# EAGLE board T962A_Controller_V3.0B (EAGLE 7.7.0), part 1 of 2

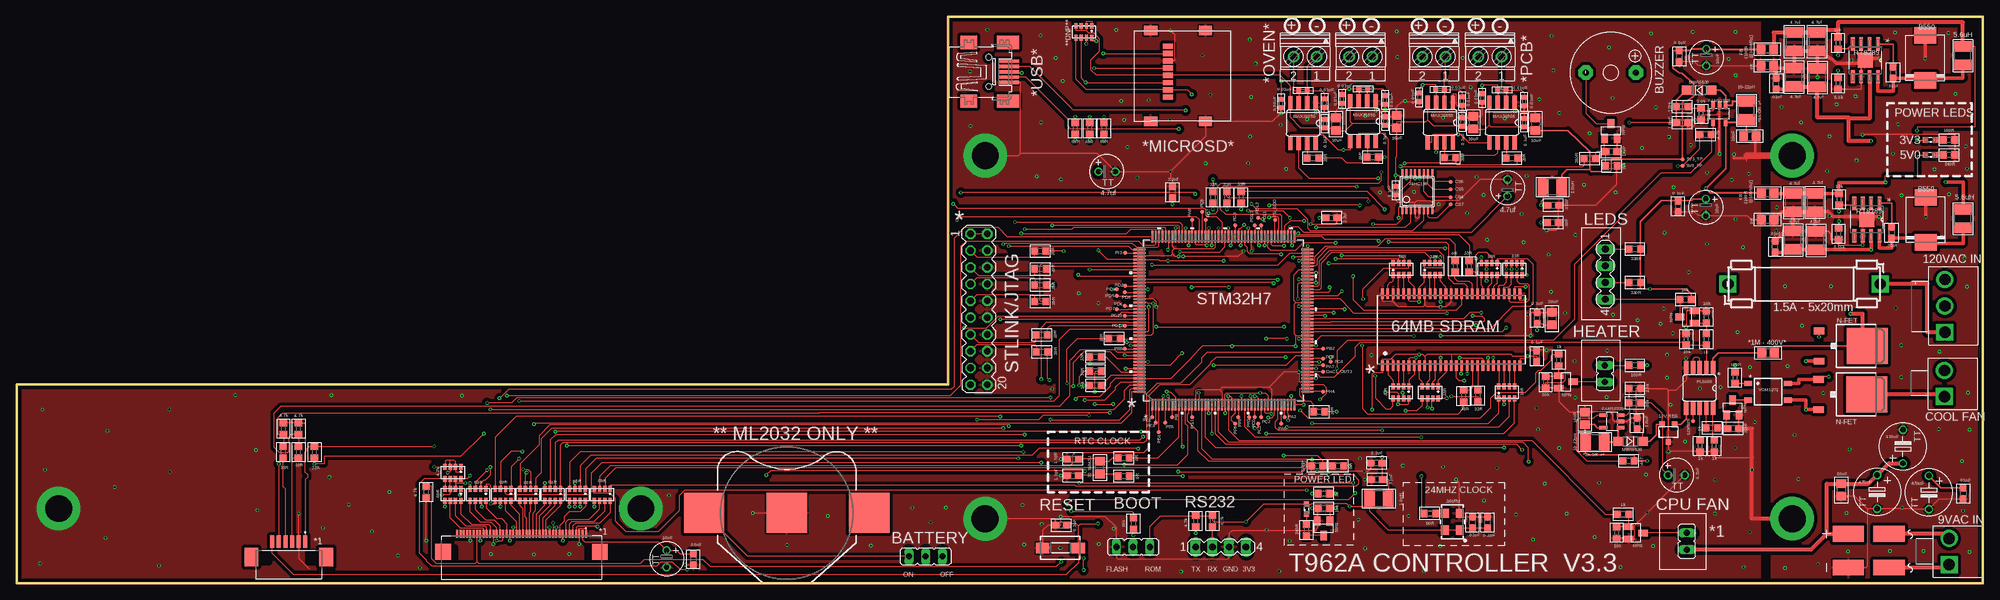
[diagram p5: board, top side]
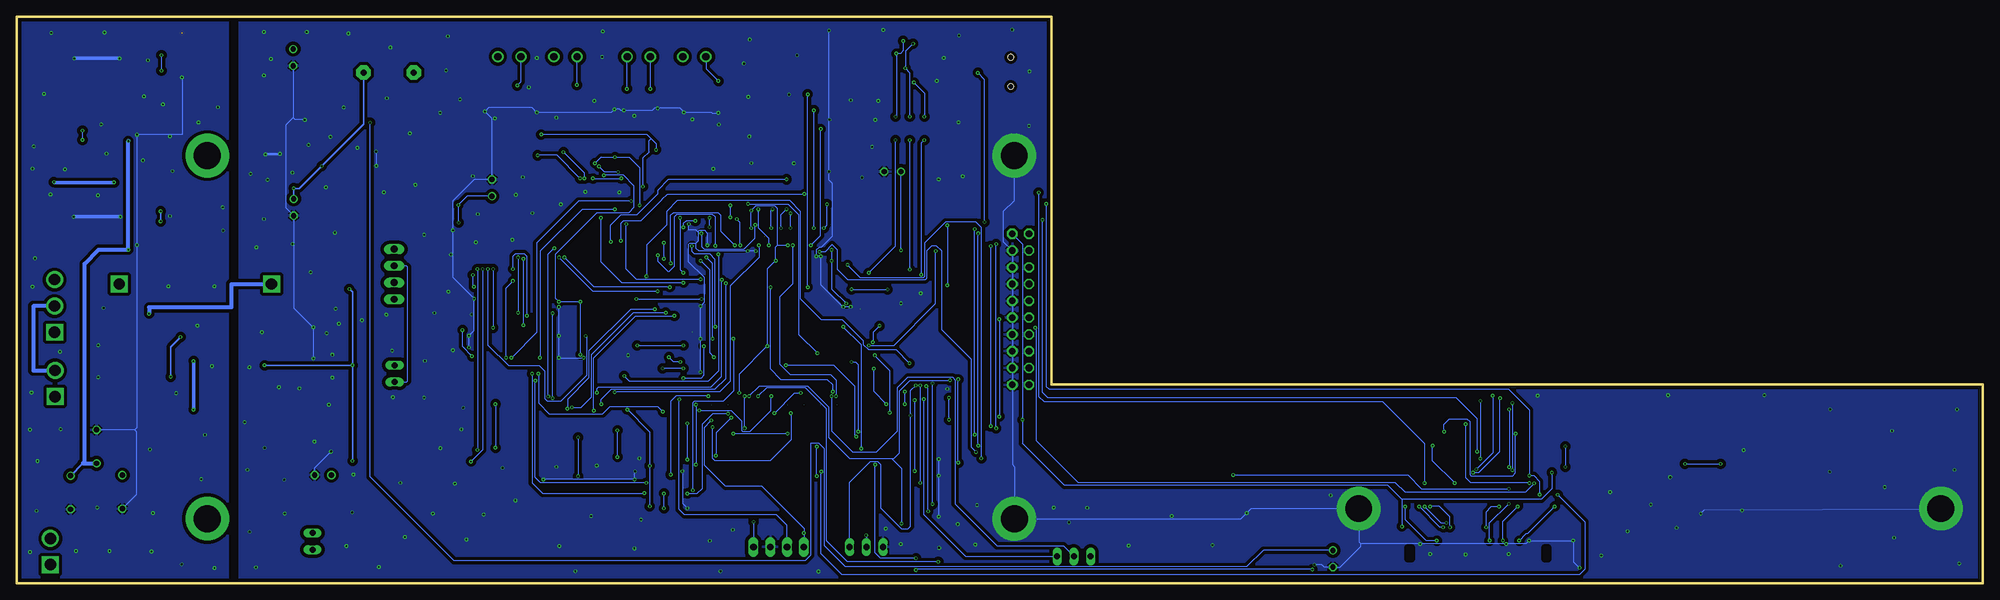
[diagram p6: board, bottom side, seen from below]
Size 297.71 x 85.85 mm. Coordinates in mm from the lower left corner, seen from the top.
Outline: 297.71,0 0,0 0,30.1 141,30.1 141,85.85 297.71,85.85 297.71,0
Copper layers (1*16): Top 0.035559375mm / dielectric 1.6mm / Bottom 0.035559375mm
Design rules "oshpark-2layer-tented": minimum track width 6mil, minimum drill 10mil, track to track 6mil, track to pad 6mil, pad to pad 6mil, via to via 6mil, smd to smd 6mil, copper to edge 15mil, drill to drill 6mil, minimum pad ring 5mil, minimum via ring 5mil, stop-mask expansion 2.5mil, vias tented up to drill 20mil, thermal gap 10mil

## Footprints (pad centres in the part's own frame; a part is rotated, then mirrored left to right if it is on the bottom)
Z4-D = smd 2.4 x 4.7: AC1 2.55,-3.1; AC2 -2.55,-3.1; VDD 2.55,3.1; VSS -2.55,3.1
BATTCON_20MM = smd 6.07 x 6.07: 1 -12.5,0; 2 0,0; 3 12.5,0
TT5D7 = drill 0.813: + -2.54,0 | drill 0.813 octagon: - 2.54,0
C0603 = smd 1.1 x 1: 1 -0.85,0; 2 0.85,0
TT2D5 = drill 0.813: + -1.27,0 | drill 0.813 octagon: - 1.27,0
C0805 = smd 1.3 x 1.5: 1 -0.95,0; 2 0.95,0
C0402 = smd 0.7 x 0.9: 1 -0.65,0; 2 0.65,0
C1210 = smd 1.6 x 2.7: 1 -1.4,0; 2 1.4,0
SOD123 = smd 1.4 x 1.4: A -1.9,0; C 1.9,0
FUSE_HOLDER_5X20MM_1.78MM = drill 1.707 square: 1 -2.565,0; 2 20.498,0.025
SOT23-3 = smd 0.8 x 0.9: 1 -0.95,-1; 2 0.95,-1; 3 0,1.659
TSSOP16 = smd 0.305 x 0.991: 1 -2.275,-2.918; 2 -1.625,-2.918; 3 -0.975,-2.918; 4 -0.325,-2.918; 5 0.325,-2.918; 6 0.975,-2.918; 7 1.625,-2.918; 8 2.275,-2.918; 9 2.275,2.918; 10 1.625,2.918; 11 0.975,2.918; 12 0.325,2.918; 13 -0.325,2.918; 14 -0.975,2.918; 15 -1.625,2.918; 16 -2.275,2.918
MOLEX_54104-4031-REV = smd 0.3 x 1.2: 1 9.75,0.6; 2 9.25,0.6; 3 8.75,0.6; 4 8.25,0.6; 5 7.75,0.6; 6 7.25,0.6; 7 6.75,0.6; 8 6.25,0.6; 9 5.75,0.6; 10 5.25,0.6; 11 4.75,0.6; 12 4.25,0.6; 13 3.75,0.6; 14 3.25,0.6; 15 2.75,0.6; 16 2.25,0.6; 17 1.75,0.6; 18 1.25,0.6; 19 0.75,0.6; 20 0.25,0.6; 21 -0.25,0.6; 22 -0.75,0.6; 23 -1.25,0.6; 24 -1.75,0.6; 25 -2.25,0.6; 26 -2.75,0.6; 27 -3.25,0.6; 28 -3.75,0.6; 29 -4.25,0.6; 30 -4.75,0.6; 31 -5.25,0.6; 32 -5.75,0.6; 33 -6.25,0.6; 34 -6.75,0.6; 35 -7.25,0.6; 36 -7.75,0.6; 37 -8.25,0.6; 38 -8.75,0.6; 39 -9.25,0.6; 40 -9.75,0.6 | smd 2.4 x 2.4: FITTING_NAIL_1 -11.85,-2.1; FITTING_NAIL_2 11.85,-2.1
KK41791-4020_2-PIN = drill 1.707 square: 1 -1.981,0 | drill 1.707: 2 1.981,0
MOLEX_52271-0679_REV = smd 0.6 x 1.9: 1 2.5,3.5; 2 1.5,3.5; 3 0.5,3.5; 4 -0.5,3.5; 5 -1.5,3.5; 6 -2.5,3.5 | smd 2.1 x 2.8: FITTING_NAIL_1 -5.65,1.15; FITTING_NAIL_2 5.65,1.15
KK41791-4020_3-PIN = drill 1.707 square: 1 -1.981,0 | drill 1.707: 2 1.981,0; 3 5.994,0
JP2_NOLABEL = drill 0.914 long: 1 -2.54,0; 2 0,0; 3 2.54,0
JP1 = drill 0.914 long: 1 0,-1.27; 2 0,1.27
L0805 = smd 1.3 x 1.5: 1 -0.95,0; 2 0.95,0
R1210 = smd 1.6 x 2.7: 1 -1.4,0; 2 1.4,0
SML0603 = smd 0.8 x 0.8: A 0.75,0; C -0.75,0
R0603 = smd 1 x 1.1: 1 -0.85,0; 2 0.85,0
R0805 = smd 1.3 x 1.5: 1 -0.95,0; 2 0.95,0
742-8NS-REV = smd 0.5 x 0.9: 1 1.2,-0.9; 2 0.4,-0.9; 3 -0.4,-0.9; 4 -1.2,-0.9; 5 -1.2,0.9; 6 -0.4,0.9; 7 0.4,0.9; 8 1.2,0.9
742-8NS = smd 0.5 x 0.9: 1 -1.2,-0.9; 2 -0.4,-0.9; 3 0.4,-0.9; 4 1.2,-0.9; 5 1.2,0.9; 6 0.4,0.9; 7 -0.4,0.9; 8 -1.2,0.9
DTSM-3 = smd 2 x 1.6: 1 -2.7,0; 2 2.7,0
YHE12-XX-7.6MM = drill 0.914 pad 2.159 octagon: + 3.81,0.025; - -3.81,0.025
MA10-2 = drill 1.016 octagon: 1 -11.43,-1.27; 2 -11.43,1.27; 3 -8.89,-1.27; 4 -8.89,1.27; 5 -6.35,-1.27; 6 -6.35,1.27; 7 -3.81,-1.27; 8 -3.81,1.27; 9 -1.27,-1.27; 10 -1.27,1.27; 11 1.27,-1.27; 12 1.27,1.27; 13 3.81,-1.27; 14 3.81,1.27; 15 6.35,-1.27; 16 6.35,1.27; 17 8.89,-1.27; 18 8.89,1.27; 19 11.43,-1.27; 20 11.43,1.27
MA04-1 = drill 1.016 long: 1 -3.81,0; 2 -1.27,0; 3 1.27,0; 4 3.81,0
SOT23-BEC = smd 1 x 1.4: B -0.95,-1.1; C 0,1.1; E 0.95,-1.1
TP06R = smd 0.6 x 0.6: TP 0,0
LQFP176-24X24MM-M = smd 1.778 x 0.279: 1 -12.725,10.75; 2 -12.725,10.25; 3 -12.725,9.75; 4 -12.725,9.25; 5 -12.725,8.75; 6 -12.725,8.25; 7 -12.725,7.75; 8 -12.725,7.25; 9 -12.725,6.75; 10 -12.725,6.25; 11 -12.725,5.75; 12 -12.725,5.25; 13 -12.725,4.75; 14 -12.725,4.25; 15 -12.725,3.75; 16 -12.725,3.25; 17 -12.725,2.75; 18 -12.725,2.25; 19 -12.725,1.75; 20 -12.725,1.25; 21 -12.725,0.75; 22 -12.725,0.25; 23 -12.725,-0.25; 24 -12.725,-0.75; 25 -12.725,-1.25; 26 -12.725,-1.75; 27 -12.725,-2.25; 28 -12.725,-2.75; 29 -12.725,-3.25; 30 -12.725,-3.75; 31 -12.725,-4.25; 32 -12.725,-4.75; 33 -12.725,-5.25; 34 -12.725,-5.75; 35 -12.725,-6.25; 36 -12.725,-6.75; 37 -12.725,-7.25; 38 -12.725,-7.75; 39 -12.725,-8.25; 40 -12.725,-8.75; 41 -12.725,-9.25; 42 -12.725,-9.75; 43 -12.725,-10.25; 44 -12.725,-10.75; 89 12.725,-10.75; 90 12.725,-10.25; 91 12.725,-9.75; 92 12.725,-9.25; 93 12.725,-8.75; 94 12.725,-8.25; 95 12.725,-7.75; 96 12.725,-7.25; 97 12.725,-6.75; 98 12.725,-6.25; 99 12.725,-5.75; 100 12.725,-5.25; 101 12.725,-4.75; 102 12.725,-4.25; 103 12.725,-3.75; 104 12.725,-3.25; 105 12.725,-2.75; 106 12.725,-2.25; 107 12.725,-1.75; 108 12.725,-1.25; 109 12.725,-0.75; 110 12.725,-0.25; 111 12.725,0.25; 112 12.725,0.75; 113 12.725,1.25; 114 12.725,1.75; 115 12.725,2.25; 116 12.725,2.75; 117 12.725,3.25; 118 12.725,3.75; 119 12.725,4.25; 120 12.725,4.75; 121 12.725,5.25; 122 12.725,5.75; 123 12.725,6.25; 124 12.725,6.75; 125 12.725,7.25; 126 12.725,7.75; 127 12.725,8.25; 128 12.725,8.75; 129 12.725,9.25; 130 12.725,9.75; 131 12.725,10.25; 132 12.725,10.75 | smd 0.279 x 1.778: 45 -10.75,-12.725; 46 -10.25,-12.725; 47 -9.75,-12.725; 48 -9.25,-12.725; 49 -8.75,-12.725; 50 -8.25,-12.725; 51 -7.75,-12.725; 52 -7.25,-12.725; 53 -6.75,-12.725; 54 -6.25,-12.725; 55 -5.75,-12.725; 56 -5.25,-12.725; 57 -4.75,-12.725; 58 -4.25,-12.725; 59 -3.75,-12.725; 60 -3.25,-12.725; 61 -2.75,-12.725; 62 -2.25,-12.725; 63 -1.75,-12.725; 64 -1.25,-12.725; 65 -0.75,-12.725; 66 -0.25,-12.725; 67 0.25,-12.725; 68 0.75,-12.725; 69 1.25,-12.725; 70 1.75,-12.725; 71 2.25,-12.725; 72 2.75,-12.725; 73 3.25,-12.725; 74 3.75,-12.725; 75 4.25,-12.725; 76 4.75,-12.725; 77 5.25,-12.725; 78 5.75,-12.725; 79 6.25,-12.725; 80 6.75,-12.725; 81 7.25,-12.725; 82 7.75,-12.725; 83 8.25,-12.725; 84 8.75,-12.725; 85 9.25,-12.725; 86 9.75,-12.725; 87 10.25,-12.725; 88 10.75,-12.725; 133 10.75,12.725; 134 10.25,12.725; 135 9.75,12.725; 136 9.25,12.725; 137 8.75,12.725; 138 8.25,12.725; 139 7.75,12.725; 140 7.25,12.725; 141 6.75,12.725; 142 6.25,12.725; 143 5.75,12.725; 144 5.25,12.725; 145 4.75,12.725; 146 4.25,12.725; 147 3.75,12.725; 148 3.25,12.725; 149 2.75,12.725; 150 2.25,12.725; 151 1.75,12.725; 152 1.25,12.725; 153 0.75,12.725; 154 0.25,12.725; 155 -0.25,12.725; 156 -0.75,12.725; 157 -1.25,12.725; 158 -1.75,12.725; 159 -2.25,12.725; 160 -2.75,12.725; 161 -3.25,12.725; 162 -3.75,12.725; 163 -4.25,12.725; 164 -4.75,12.725; 165 -5.25,12.725; 166 -5.75,12.725; 167 -6.25,12.725; 168 -6.75,12.725; 169 -7.25,12.725; 170 -7.75,12.725; 171 -8.25,12.725; 172 -8.75,12.725; 173 -9.25,12.725; 174 -9.75,12.725; 175 -10.25,12.725; 176 -10.75,12.725
SOT23-5L = smd 0.55 x 1.2: 1 -0.95,-1.3; 2 0,-1.3; 3 0.95,-1.3; 4 0.95,1.3; 5 -0.95,1.3
SO08 = smd 0.66 x 2.032: 1 -1.905,-3.073; 2 -0.635,-3.073; 3 0.635,-3.073; 4 1.905,-3.073; 5 1.905,3.073; 6 0.635,3.073; 7 -0.635,3.073; 8 -1.905,3.073
SOIC127P600X175-9N = smd 1.981 x 0.559: 1 -2.464,1.905; 2 -2.464,0.635; 3 -2.464,-0.635; 4 -2.464,-1.905; 5 2.464,-1.905; 6 2.464,-0.635; 7 2.464,0.635; 8 2.464,1.905 | smd 2.286 x 2.286: 9 0,0
DO214AB-SMC = smd 2.5 x 3.3: A 3.4,0; C -3.4,0
SOP10 = smd 0.66 x 2.032: 1 -2.057,-3.073; 2 -1.041,-3.073; 3 -0.025,-3.073; 4 0.991,-3.073; 5 2.007,-3.073; 6 2.007,3.073; 7 0.991,3.073; 8 -0.025,3.073; 9 -1.041,3.073; 10 -2.057,3.073
DPACK_3 = smd 1 x 1.6: 1 -2.28,-4.8; 3 2.28,-4.8 | smd 5.4 x 6.2: 4 0,2.5
SOP04 = smd 0.8 x 1.2: 1 -1.27,-3; 2 1.27,-3; 3 1.27,3; 4 -1.27,3
TSOP54 = smd 0.4 x 1.6: 1 -10.4,-5.45; 2 -9.6,-5.45; 3 -8.8,-5.45; 4 -8,-5.45; 5 -7.2,-5.45; 6 -6.4,-5.45; 7 -5.6,-5.45; 8 -4.8,-5.45; 9 -4,-5.45; 10 -3.2,-5.45; 11 -2.4,-5.45; 12 -1.6,-5.45; 13 -0.8,-5.45; 14 0,-5.45; 15 0.8,-5.45; 16 1.6,-5.45; 17 2.4,-5.45; 18 3.2,-5.45; 19 4,-5.45; 20 4.8,-5.45; 21 5.6,-5.45; 22 6.4,-5.45; 23 7.2,-5.45; 24 8,-5.45; 25 8.8,-5.45; 26 9.6,-5.45; 27 10.4,-5.45; 28 10.4,5.45; 29 9.6,5.45; 30 8.8,5.45; 31 8,5.45; 32 7.2,5.45; 33 6.4,5.45; 34 5.6,5.45; 35 4.8,5.45; 36 4,5.45; 37 3.2,5.45; 38 2.4,5.45; 39 1.6,5.45; 40 0.8,5.45; 41 0,5.45; 42 -0.8,5.45; 43 -1.6,5.45; 44 -2.4,5.45; 45 -3.2,5.45; 46 -4,5.45; 47 -4.8,5.45; 48 -5.6,5.45; 49 -6.4,5.45; 50 -7.2,5.45; 51 -8,5.45; 52 -8.8,5.45; 53 -9.6,5.45; 54 -10.4,5.45
MOLEX:47219-2001 = smd 1.45 x 2: G1 13.75,0; G2 13.75,8.3; G3 0,8.3; G4 0,0 | smd 0.8 x 1.5: P1 10.08,2.6; P2 8.98,2.6; P3 7.88,2.6; P4 6.78,2.6; P5 5.68,2.6; P6 4.58,2.6; P7 3.48,2.6; P8 2.38,2.6
1751248 = drill 1.1 pad 1.7: 1 -1.75,-0.1; 2 1.75,-0.1
32005-201 = smd 3.1 x 0.5: 1 3,1.6; 2 3,0.8; 3 3,0; 4 3,-0.8; 5 3,-1.6 | smd 2.5 x 2: M1 -3,-4.45; M2 -3,4.45 | smd 3.3 x 2: M3 2.9,4.45; M4 2.9,-4.45 | hole 0.9: 0,2.2; 0,-2.2
OSCILLATOR-SMD-5X3.2 = smd 1.397 x 1.194: 1 -1.27,-1.1; 2 1.27,-1.1; 3 1.27,1.1; 4 -1.27,1.1

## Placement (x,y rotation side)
B1  Z4DGP406L-HF  [Z4-D]  280.39,4.93 90 top
BT1  [BATTCON_20MM]  116.61,10.64 0 top
C1  470uF  [TT5D7]  289.53,13.74 270 top
C2  0.1uF  [C0603]  205.89,18.21 180 top
C3  10uF  [TT2D5]  255.83,79.65 270 top
C4  0.01uF  [C0603]  205.97,15.72 180 top
C5  .1uf  [C0603]  158.17,8.79 180 top
C6  470uF  [TT5D7]  281.69,13.84 270 top
C7  10uF  [C0805]  276.28,14.12 270 top
C8  0.1uF  [C0603]  222.71,9.22 90 top
C9  2.2uF  [C0603]  175.01,59.23 90 top
C10  2.2uF  [C0603]  199.09,55.37 0 top
C11  10uF  [TT2D5]  255.75,56.95 270 top
C12  0.01uF  [C0603]  220.42,9.22 90 top
C13  .1uf  [C0603]  230.2,40.18 90 top
C14  .1uf  [C0603]  230.15,34.39 90 top
C15  1.0uF  [C0603]  252.17,69.77 0 top
C16  0.1uF  [C0603]  251.71,79.83 270 top
C17  0.1uF  [C0603]  251.54,57.1 270 top
C18  10uF  [C0805]  262.41,67.72 0 top
C19  0.01uF  [C0402]  203.89,74.9 180 top
C20  0.01uF  [C0402]  200.66,73.36 90 top
C21  0.01uF  [C0402]  207.19,73.2 90 top
C22  0.01uF  [C0402]  215.52,74.8 180 top
C23  0.01uF  [C0402]  212.37,73.61 90 top
C24  1.5pf  [C0603]  159.92,18.82 0 top
C25  1.5pf  [C0603]  159.92,16.31 0 top
C26  0.1uF  [C0603]  232.61,54.64 0 top
C27  22nf  [C0603]  259.89,23.44 180 top
C28  470uF  [TT5D7]  285.6,20.7 90 top
C29  0.01uF  [C0603]  232.66,57.28 0 top
C30  1.0uF  [C0603]  245.34,24.23 90 top
C31  0.1uF  [C0402]  208.79,59.49 270 top
C32  0.1uF  [C0402]  207.21,70.03 270 top
C33  0.1uF  [C0402]  218.87,69.88 270 top
C34  10uF  [C0805]  237.44,24.99 90 top
C35  0.1uF  [C0402]  228.24,69.77 270 top
C36  0.1uF  [C0402]  198.07,69.62 270 top
C37  4.7uF  [TT2D5]  251.31,16.38 0 top
C38  4.7uF  [TT2D5]  165.07,62.36 0 top
C39  4.7uF  [TT2D5]  225.73,59.89 90 top
C40  10uF  [TT2D5]  98.42,3.71 270 top
C41  .01uF  [C0603]  102.44,3.63 270 top
C42  10uF  [C0805]  232.46,40.08 90 top
C45  DNP  [C0603]  241.43,65.38 180 top
C46  10uF  [C0805]  199.72,69.55 270 top
C47  10uF  [C0805]  208.94,69.9 270 top
C48  0.01uF  [C0402]  191.44,72.67 90 top
C49  10uF  [C0805]  220.55,69.77 270 top
C50  .01uF  [C0603]  294.72,13.61 270 top
C51  10uF  [C0805]  229.97,69.55 270 top
C52  0.01uF  [C0402]  198.04,72.75 90 top
C53  0.01uF  [C0402]  194.77,74.63 180 top
C54  .01uF  [C0603]  284.1,77.37 270 top
C55  .01uF  [C0603]  266.4,75.69 90 top
C56  4.7uF  [C1210]  272.64,76.58 90 top
C57  4.7uF  [C1210]  269.09,76.66 90 top
C58  47uf  [C1210]  269.14,82.02 270 top
C59  47uf  [C1210]  272.59,82.02 270 top
C60  0.01uF  [C0402]  218.85,73.03 90 top
C61  0.01uF  [C0402]  224.89,74.73 180 top
C62  0.01uF  [C0402]  221.89,73.51 90 top
C63  0.01uF  [C0402]  228.24,72.95 90 top
C88  .01uF  [C0603]  283.87,53.11 270 top
C89  .01uF  [C0603]  266.24,50.98 90 top
C90  4.7uF  [C1210]  272.41,51.92 90 top
C91  4.7uF  [C1210]  268.94,51.99 90 top
C92  47uf  [C1210]  272.29,57.68 270 top
C93  47uf  [C1210]  269.01,57.63 270 top
D1  MBR0520LT  [SOD123]  254.71,74.68 180 top
D2  MBR0520LT  [SOD123]  244.35,21.49 0 top
F1  FUSE  [FUSE_HOLDER_5X20MM_1.78MM]  261.67,45.31 0 top
IC1  TLV760SOT-23-3  [SOT23-3]  250.09,23.06 180 top
IC2  74138TSSOP  [TSSOP16]  212.06,59.31 0 top
J1  54104-4031MOLEX_54101_4031-REV  [MOLEX_54104-4031-REV]  76.45,6.86 0 top
J2  0026604020  [KK41791-4020_2-PIN]  292.58,4.8 90 top
J3  52271-0679_REVMOLEX_52271-0679-REV  [MOLEX_52271-0679_REV]  41.22,2.84 0 top
J4  0026604030  [KK41791-4020_3-PIN]  291.95,40.01 90 top
J5  0026604020  [KK41791-4020_2-PIN]  291.87,30.25 90 top
JP1  [JP2_NOLABEL]  169.04,5.49 0 top
JP2  [JP1]  240.46,31.75 0 top
JP3  [JP1]  252.88,6.35 180 top
JP4  [JP2_NOLABEL]  137.64,4.06 180 top
L1  100R@100Mhz  [L0805]  265.1,59.11 180 top
L2  5.6uH  [R1210]  294.67,79.91 90 top
L3  5.6uH  [R1210]  294.69,55.22 90 top
L4  10uH  [R1210]  206.27,12.85 0 top
L6  100R@100Mhz  [L0805]  265.07,80.92 180 top
L8  10uH  [R1210]  232.54,60.02 180 top
LED1  [SML0603]  289.74,67.16 180 top
LED2  [SML0603]  195.3,11.23 90 top
LED5  [SML0603]  289.71,64.87 180 top
Q1  32.768Khz  [C0805]  164.01,17.53 90 top
R1  20R  [R0603]  154.99,50.32 180 top
R2  100R  [R0603]  292.56,67.16 0 top
R3  20R  [R0603]  155.02,47.62 180 top
R4  20R  [R0603]  155.02,45.16 180 top
R5  240R  [R0603]  292.58,64.87 180 top
R6  0R  [R0805]  265.1,55.12 180 top
R7  20R  [R0603]  154.99,42.7 180 top
R8  20R  [R0603]  155.19,37.62 180 top
R9  20R  [R0603]  155.24,35.05 180 top
R10  10k  [R0603]  163.35,29.97 0 top
R11  10k  [R0603]  169.09,9.04 90 top
R12  33R  [R0603]  219.94,48.03 270 top
R13  0R  [R0603]  167.61,19 180 top
R14  50R  [R0603]  213.97,10.57 0 top
R15  0R  [R0603]  217.78,48.03 270 top
R16  33R  [R0603]  181.13,58.45 90 top
R17  20R  [R0603]  205.33,64.54 180 top
R18  20R  [R0603]  217.04,64.47 180 top
R19  20R  [R0603]  226.39,64.39 180 top
R20  1k  [R0603]  256.67,23.52 0 top
R21  10k  [R0603]  252.78,36.98 90 top
R22  100R  [R0603]  245.01,33.02 180 top
R23  4.7k  [R0603]  178.51,9.4 270 top
R24  4.7k  [R0603]  181.05,9.4 270 top
R25  100R  [R0603]  260.17,31.14 90 top
R26  2.0k  [R0603]  245.01,29.51 0 top
R27  20R  [R0603]  196.27,64.41 180 top
R28  2k  [R0603]  197.92,13.59 180 top
R29  240R  [R0603]  195.3,8.08 270 top
R30  10k  [R0603]  197.92,11.35 0 top
R31  10K  [R0603]  275.77,81.81 270 top
R32  5.6k  [R0603]  275.77,75.69 270 top
R33  10K  [R0603]  275.92,58.17 270 top
R34  3.16k  [R0603]  275.84,52.91 270 top
R35  10k  [R0603]  241.45,63.22 180 top
R36  4k7  [R0603]  42.7,23.42 90 top
R37  4K7  [R0603]  255.7,67.97 0 top
R38  4k7  [R0603]  62.03,13.79 270 top
R39  0R  [R0805]  265.07,78.41 180 top
R40  1M  [R0805]  265.18,34.9 0 top
R41  4k7  [R0603]  40.41,23.42 90 top
R42  33R  [R0603]  221.23,28.4 90 top
R43  390R  [R0603]  238.18,64.34 180 top
R44  10k  [R0603]  255.83,40.34 90 top
R45  120k  [R0603]  252.17,72.21 180 top
R46  4K7  [R0603]  244.04,18.54 180 top
R47  80k  [R0603]  245.01,27.3 0 top
R48  68R  [R0603]  164.64,68.91 90 top
R49  68R  [R0603]  162.48,68.91 90 top
R50  68R  [R0603]  160.27,68.91 90 top
R51  33R  [R0603]  42.7,19.86 270 top
R52  1k  [R0603]  243.2,10.44 0 top
R53  10k  [R0603]  242.24,7.65 90 top
R54  1k  [R0603]  233.48,33.83 270 top
R55  10k  [R0603]  231.5,30.45 90 top
R56  330R  [R0603]  245.01,50.62 180 top
R57  330R  [R0603]  245.01,45.54 180 top
R58  10k  [R0603]  252.7,42.98 0 top
R59  0R  [R0603]  200.08,17.78 0 top
R60  DNP  [R0603]  196.93,17.78 0 top
R61  2.0k  [R0603]  255.04,71.07 270 top
R62  1k  [R0603]  254.86,20.8 90 top
R63  1k  [R0603]  257.02,20.8 90 top
R64  1k  [R0603]  255.83,36.98 90 top
R65  33R  [R0603]  40.39,19.86 270 top
R66  4k7  [R0603]  45.11,19.86 90 top
R67  33R  [R0603]  219.07,28.37 90 top
R68  33R  [R0603]  166.22,37.08 180 top
R69  33R  [R0603]  197.21,25.98 0 top
R70  33R  [R0603]  163.35,34.29 180 top
R71  33R  [R0603]  163.35,32.13 180 top
R72  33R  [R0603]  183.26,58.45 90 top
R73  33R  [R0603]  185.39,58.45 90 top
R74  0R  [R0603]  167.61,16.23 180 top
RN1  33R  [742-8NS-REV]  209.63,47.57 0 top
RN2  33R  [742-8NS-REV]  214.35,47.57 0 top
RN3  33R  [742-8NS-REV]  214.02,28.91 180 top
RN4  33R  [742-8NS-REV]  209.6,28.91 180 top
RN5  33R  [742-8NS]  225.6,28.91 0 top
RN6  4.7k  [742-8NS]  66.07,16.74 180 top
RN7  33R  [742-8NS]  226.75,47.57 180 top
RN8  33R  [742-8NS]  222.96,47.57 180 top
RN11  **DNP**  [742-8NS]  161.59,83.52 180 top
RN12  68R  [742-8NS-REV]  88.67,13.41 180 top
RN13  68R  [742-8NS-REV]  84.94,13.41 180 top
RN14  68R  [742-8NS-REV]  81.18,13.41 180 top
RN15  68R  [742-8NS-REV]  77.42,13.41 180 top
RN16  68R  [742-8NS-REV]  73.66,13.41 180 top
RN17  68R  [742-8NS-REV]  69.88,13.41 180 top
RN18  68R  [742-8NS-REV]  66.07,13.41 180 top
S1  DTSM-3  [DTSM-3]  158.04,5.36 0 top
SG1  YHE12-XX7.6MM  [YHE12-XX-7.6MM]  241.38,77.34 0 top
SV1  [MA10-2]  145.69,41.5 270 top
SV3  [MA04-1]  240.54,46.81 270 top
SV5  RS232  [MA04-1]  182.32,5.49 0 top
T1  BC817-16LT1SMD  [SOT23-BEC]  241.38,68.5 0 top
T3  BC817-16LT1SMD  [SOT23-BEC]  197.89,8.33 180 top
T4  BC817-16LT1SMD  [SOT23-BEC]  245.16,7.62 270 top
T5  BC817-16LT1SMD  [SOT23-BEC]  234.57,30.51 270 top
T6  BC817-16LT1SMD  [SOT23-BEC]  259.82,26.62 0 top
T7  BC817-16LT1SMD  [SOT23-BEC]  252.93,40.34 90 top
TP1  TPTP06R  [TP06R]  187.48,25.17 0 top
TP2  TPTP06R  [TP06R]  187.99,24.16 0 top
TP3  TPTP06R  [TP06R]  198.93,33.53 0 top
TP4  TPTP06R  [TP06R]  252.22,64.21 0 top
TP5  TPTP06R  [TP06R]  188.47,25.17 0 top
TP6  TPTP06R  [TP06R]  217.12,57.4 0 top
TP7  TPTP06R  [TP06R]  217.12,60.83 0 top
TP8  TPTP06R  [TP06R]  217.12,59.66 0 top
TP9  TPTP06R  [TP06R]  217.12,58.5 0 top
TP10  TPTP06R  [TP06R]  197.79,34.04 90 top
TP11  TPTP06R  [TP06R]  167.77,42.01 0 top
TP12  TPTP06R  [TP06R]  166.55,41.53 0 top
TP14  TPTP06R  [TP06R]  173.94,24.31 0 top
TP15  TPTP06R  [TP06R]  171.96,25.17 0 top
TP16  TPTP06R  [TP06R]  179.5,56.29 90 top
TP17  TPTP06R  [TP06R]  180.04,55.02 90 top
TP18  TPTP06R  [TP06R]  197.79,32.03 0 top
TP19  TPTP06R  [TP06R]  197.79,33.02 0 top
TP21  TPTP06R  [TP06R]  177.98,55.02 0 top
TP22  TPTP06R  [TP06R]  197.79,35.51 0 top
TP23  TPTP06R  [TP06R]  167.77,35.53 0 top
TP24  TPTP06R  [TP06R]  167.82,45.03 0 top
TP25  TPTP06R  [TP06R]  166.55,44.53 0 top
TP26  TPTP06R  [TP06R]  167.77,39.04 0 top
TP27  TPTP06R  [TP06R]  252.22,63.2 0 top
TP28  TPTP06R  [TP06R]  253.8,24.54 0 top
TP29  TPTP06R  [TP06R]  191.47,24.16 0 top
TP30  TPTP06R  [TP06R]  191.99,25.17 0 top
TP31  TPTP06R  [TP06R]  167.77,44.04 0 top
TP32  TPTP06R  [TP06R]  166.55,43.56 0 top
TP33  TPTP06R  [TP06R]  184.48,24.16 0 top
TP34  TPTP06R  [TP06R]  184.96,25.17 0 top
TP35  TPTP06R  [TP06R]  167.77,40.54 0 top
TP36  TPTP06R  [TP06R]  197.79,29.03 0 top
TP39  TPTP06R  [TP06R]  184.48,54.23 0 top
TP40  TPTP06R  [TP06R]  167.82,50.04 0 top
TP41  TPTP06R  [TP06R]  174.98,25.17 0 top
TP42  TPTP06R  [TP06R]  188.47,54.23 0 top
TP43  TPTP06R  [TP06R]  187.96,55.37 0 top
TP44  TPTP06R  [TP06R]  187.48,54.23 0 top
TP45  TPTP06R  [TP06R]  177.98,25.17 0 top
TP46  TPTP06R  [TP06R]  190.55,55.02 0 top
TP47  TPTP06R  [TP06R]  186.61,25.17 0 top
TP48  TPTP06R  [TP06R]  172.47,24.31 0 top
TP49  TPTP06R  [TP06R]  172.95,22.89 0 top
U1  STM32H7X3IITLQFP176-24X24MM-M  [LQFP176-24X24MM-M]  182.73,39.78 90 top
U$1  FAN5333ABSOT23-5  [SOT23-5L]  257.81,71.15 180 top
U$2  INDUCTOR-GENERIC1210-PKG  [R1210]  261.9,71.63 90 top
U$3  MAX31855  [SO08]  194.77,69.7 180 top
U$4  MAX31855  [SO08]  203.83,69.98 180 top
U$5  MAX31855  [SO08]  215.54,69.8 180 top
U$6  MAX31855  [SO08]  224.89,69.8 180 top
U$7  RT8289  [SOIC127P600X175-9N]  279.91,79.22 270 top
U$8  DIODE-SMC  [DO214AB-SMC]  288.98,79.58 90 top
U$9  RT8289  [SOIC127P600X175-9N]  280.14,55.09 270 top
U$10  FL5160SOP10  [SOP10]  254.79,29.57 180 top
U$11  N-PWR-MOSFETDPAK3  [DPACK_3]  277.65,28.6 270 top
U$12  N-PWR-MOSFETDPAK3  [DPACK_3]  277.67,35.94 270 top
U$13  DIODE-SMC  [DO214AB-SMC]  289.05,55.07 90 top
U$14  VOM1271  [SOP04]  265.15,29.01 270 top
U$15  AS4C32M16SB  [TSOP54]  217.2,38.4 0 top
U$16  INDUCTOR-GENERIC1210-PKG  [R1210]  238.94,21.36 0 top
U$17  FAN5333ABSOT23-5  [SOT23-5L]  241.55,24.51 90 top
U$19  MOLEX-47219-2001  [MOLEX:47219-2001]  171.7,83.72 270 top
X1  1751248  [1751248]  195.1,79.68 180 top
X2  1751248  [1751248]  203.5,79.68 180 top
X3  1751248  [1751248]  214.6,79.68 180 top
X4  1751248  [1751248]  223.09,79.68 180 top
X5  MINI-USB-32005-201  [32005-201]  147.19,77.47 0 top
Y1  OSCILLATORSMD-5X3  [OSCILLATOR-SMD-5X3.2]  217.37,9.32 90 top

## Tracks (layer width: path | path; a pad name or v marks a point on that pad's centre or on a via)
3V3_VDD  (via drill 0.25 pad 0.51)
  Top 0.152: 204.87,11.66 v201.85,11.66 201.37,12.14 196.1,12.14 195.94,11.98 LED2.A 188.81,11.98 v186.13,9.3 181.25,9.3 181.05,9.5 R24.1 R23.1 173.19,10.25 171.58,8.64 JP1.3 | 204.87,11.66 204.87,10.9 207.72,8.05 Y1.4 Y1.1 218.47,8.37 C12.1 C8.1 | 213.64,70.16 213.33,69.85 208.94,69.85 208.94,69.38 | 208.94,69.38 C32.2 207.21,69.62 202.23,69.62 | 161.99,83.67 161.19,83.67 | 161.19,83.67 160.39,83.67 RN11.4 | 161.19,83.67 RN11.3 | 161.99,83.67 162.35,83.31 163.14,83.31 163.96,82.5 163.96,80.62 162.66,79.32 162.66,77.75 163.47,76.94 U$19.P4 191.26,76.94 192.86,75.34 U$3.4 192.86,70.57 194.46,68.97 C36.2 199.72,68.97 C46.2 201.21,68.59 202.23,69.62 | v228.75,34.39 230.15,34.39 C14.1 | v228.75,34.39 226.57,34.39 226.31,34.65 217.2,34.65 | 217.2,34.65 213.51,34.65 213.21,34.34 | v162.36,25.43 155.37,25.43 154.71,24.77 v145.42,24.77 | 217.2,34.65 U$15.14 | v208.79,61.8 208.79,64.47 208.94,64.62 C47.2 208.94,69.38 | v208.79,61.8 C31.1 | 213.64,70.16 214.57,69.22 C33.2 219.56,69.22 219.56,68.82 C49.2 222.36,68.82 222.96,69.43 | 222.96,69.43 223.27,69.12 C35.2 228.93,69.12 228.93,68.59 C51.2 | 44.04,20.19 43.74,20.5 43.74,24.07 43.54,24.27 R36.2 R41.2 | 208.1,33.98 208.76,34.65 v212.34,34.65 212.9,34.65 213.21,34.34 | 204.87,11.66 L4.1 | 44.04,20.19 43.74,19.89 43.74,16.82 44.04,16.51 44.04,16.08 43.72,15.76 J3.1 | 44.04,20.19 44.04,20.5 44.26,20.71 R66.2 63.22,20.71 v63.22,20.73 | v230.2,38.35 C13.1 230.94,39.33 231.14,39.13 C42.1 | 161.99,83.67 RN11.2 161.99,85.11 162.79,85.11 RN11.1 | 65.2,16.69 v65.28,16.76 65.51,16.76 65.76,17.02 65.76,17.64 RN6.3 65.67,18.62 65.68,18.64
  Top 0.152: 222.96,69.43 222.98,69.44 222.99,69.44 U$6.4 | 202.23,69.62 201.93,69.93 U$4.4 | 213.64,70.16 U$5.4 | 65.68,18.64 65.07,18.64 64.87,18.43 RN6.4 v63.22,17.63 | 65.68,18.64 66.26,18.64 66.47,18.44 RN6.2 66.47,16.84 67.27,16.84 RN6.1 | SV1.2 SV1.1 | v208.79,61.8 209.27,61.8 209.27,61.7 209.47,61.49 209.79,61.49 IC2.16 | v205.23,26.31 205.23,31.67 205.44,31.88 206.8,31.88 U$15.1 206.8,33.98 208.1,33.98 | v228.75,34.39 228.35,33.98 227.6,33.98 U$15.27 | 213.21,34.34 213.21,34.01 213.2,34 U$15.9 | 208.1,33.98 208.41,33.98 208.41,32.95 U$15.3 | v87.96,8.61 84.91,8.61 84.7,8.4 J1.4 | v212.34,42.65 210.97,42.65 210.8,42.82 U$15.49 | v201.85,17.78 R59.2 | v161.57,29.97 R10.1 | v215.6,42.65 | v215.6,42.65 U$15.43
  Top 0.203: 253.9,73.81 252.93,73.1 252.43,73.1 252.17,72.8 TP4.TP 241.48,64.21 241.48,62.64 241.3,62.33 238.38,62.33 238.18,62.64 | C51.2 234.9,68.59 238.18,65.42 238.18,62.64 | 238.18,62.64 234.75,62.64 233.94,61.93 L8.1
  Top 0.254: C16.1 250.72,80.68 250.72,78.05 251.79,77.24 252.15,77.24 253.9,75.64 253.9,73.81
  Top 0.305: L6.2 C3.+ 253.57,80.92 253.33,80.68 C16.1
  Bottom 0.152: JP1.3 171.58,15.27 168.4,18.44 167.34,18.44 166.93,18.03 166.93,11.41 163.75,8.23 162.76,8.23 162.36,8.64 v162.36,25.43 162.36,29.19 v161.57,29.97 | 87.96,12.68 90.12,14.83 139.07,14.83 145.42,21.18 v145.42,24.77 145.42,51.38 SV1.2 | v65.28,16.76 65.28,14.28 66.88,12.68 87.96,12.68 | v208.79,61.8 205.79,61.8 204.19,60.2 204.19,56.95 205,56.13 209.78,56.13 216.08,49.84 216.08,43.13 v215.6,42.65 v212.34,42.65 v212.34,34.65 | v186.13,9.3 SV5.4 | v228.75,34.39 230.2,35.84 v230.2,38.35 | v205.23,26.31 201.85,22.94 v201.85,17.78 v201.85,11.66 | 87.96,12.68 v87.96,8.61 | v63.22,20.73 v63.22,17.63
5V0_VDD  (via drill 0.25 pad 0.51)
  Top 0.152: R37.1 254.85,65.83 TP27.TP v251.51,63.2 | 261.9,69.72 U$2.1 261.9,70.67 | 261.9,67.72 C18.1 | v246.84,33.02 R22.1 | 237.54,24.04 C34.1
  Top 0.203: 261.9,69.72 261.9,67.72
  Top 0.254: 237.54,24.04 238.86,24.04 239.34,23.56 U$17.5 | U$16.1 237.54,19.74 237.94,19.46 244.89,19.46 R46.1 v246.84,18.54 | R58.2 253.55,43.78 252.76,44.58 v247.32,44.58 246.01,44.58 245.86,44.73 R57.1 R56.1 245.86,54.76 249.05,57.95 C17.1 253.53,57.95 253.8,58.22 C11.+ | U$1.5 258.76,62.82 v255.75,59.82 | v260.17,33.02 R25.2
  Top 0.305: 264.1,59.06 L1.2 256.46,59.11 v255.75,59.82 | U$16.1 237.54,24.04 | U$1.5 261.9,69.84 261.9,69.72
  Bottom 0.203: SG1.+ 245.19,69.52 v251.51,63.2 254.89,59.82 v255.75,59.82
  Bottom 0.254: C11.+ v255.75,59.82 | v246.84,33.02 v246.84,18.54 | v246.84,33.02 v260.17,33.02 | v247.32,44.58 246.84,44.09 v246.84,33.02
12V0_VDD
  Top 0.203: U$10.6 252.78,24.87 251.98,24.06 IC1.1
!CS0  (via drill 0.25 pad 0.51)
  Top 0.152: v206.15,61.32 195.73,61.32 194.13,62.92 U$3.6 | v210.44,61.32 | v210.44,61.32 IC2.15
  Bottom 0.152: v210.44,61.32 v206.15,61.32
!CS1
  Top 0.152: U$4.6 203.2,68.15 206.78,68.15 207.59,67.34 207.59,59.84 208,59.44 209.5,59.44 211.09,61.03 IC2.14
!CS2  (via drill 0.25 pad 0.51)
  Top 0.152: v214.91,65.3 U$5.6 | v211.73,61.32 v211.74,61.32 IC2.13
  Bottom 0.152: v211.73,61.32 211.73,62.13 v214.91,65.3
!CS3  (via drill 0.25 pad 0.51)
  Top 0.152: v218.82,64.82 223.85,64.82 224.26,65.23 U$6.6 | v212.39,61.32 IC2.12
  Bottom 0.152: v212.39,61.32 215.9,64.82 v218.82,64.82
!CS4
  Top 0.152: TP9.TP 213.84,58.5 213.04,59.3 IC2.11
!CS5
  Top 0.152: TP8.TP 214.5,59.67 213.69,60.48 IC2.10
!CS6
  Top 0.152: TP7.TP 214.76,60.83 214.34,61.25 IC2.9
!CS7
  Top 0.152: TP6.TP 215.06,55.35 213.89,55.35 213.69,55.55 IC2.7
!TP_INT  (via drill 0.25 pad 0.51)
  Top 0.152: v70.76,22.68 67.27,19.19 46.58,19.19 46.58,18.09 v45.11,18.09 R66.1 | v170.28,22.99 v81.58,22.99 | v39.73,18.09 39.73,6.83 39.72,6.83 J3.5 | v171.3,33.53 U1.167
  Bottom 0.152: v81.58,22.99 v81.59,23 81.59,24.08 80.78,24.89 78.11,24.89 77.7,24.49 77.7,16.49 77.5,16.28 71.17,16.28 70.76,16.69 v70.76,22.68 | v171.3,33.53 170.69,33.53 170.28,33.12 v170.28,22.99 | v45.11,18.09 v39.73,18.09
A0  (via drill 0.25 pad 0.51)
  Top 0.152: v196.16,18.75 181.08,18.75 179.48,20.34 U1.16 | v196.16,24.21 222.81,24.21 224.4,25.8 RN5.1
  Bottom 0.152: v196.16,24.21 v196.17,24.2 v196.17,18.75 v196.16,18.75
A1  (via drill 0.25 pad 0.51)
  Top 0.152: v225.2,20.52 181.58,20.52 179.98,22.13 U1.17 | v225.2,27.13 RN5.2
  Bottom 0.152: v225.2,27.13 v225.2,20.52
A2  (via drill 0.25 pad 0.51)
  Top 0.152: v192.33,23.65 224.41,23.65 226,25.24 RN5.3 | v180.47,25.76 180.48,25.77 U1.18
  Bottom 0.152: v180.47,25.76 180.47,21.72 183.64,18.54 191.92,18.54 192.33,18.95 v192.33,23.65
A3  (via drill 0.25 pad 0.51)  (1 unrouted)
  Top 0.152: v180.98,22.68 v180.98,22.69 U1.19 | v189.18,22.68 225.2,22.68 226.8,24.29 RN5.4
  Bottom 0.152: v189.18,22.68 v180.98,22.68
A4  (via drill 0.25 pad 0.51)
  Top 0.152: v227.94,20.19 227.13,21.01 183.08,21.01 181.48,22.61 U1.20 | v227.94,47.6 v227.95,47.61 RN7.1
  Bottom 0.152: v227.94,47.6 v227.94,20.19
A5  (via drill 0.25 pad 0.51)
  Top 0.152: v228.9,18.44 228.9,20.5 228.09,21.31 183.57,21.31 181.98,22.9 U1.21 | v227.15,47.6 v227.15,47.61 RN7.2
  Bottom 0.152: v227.15,47.6 227.15,20.19 v228.9,18.44
A6  (via drill 0.25 pad 0.51)
  Top 0.152: v226.34,47.6 v226.35,47.61 RN7.3 | v211.56,37.47 197.51,37.47 196.57,36.53 U1.60
  Bottom 0.152: v211.56,37.47 211.38,37.29 211.38,31.5 215.34,27.53 217.3,27.53 217.7,27.94 217.7,32.08 218.5,32.88 223.16,32.88 226.34,36.05 v226.34,47.6
A7  (via drill 0.25 pad 0.51)  (1 unrouted)
  Top 0.152: v225.55,38.71 224.87,38.03 U1.63 | v225.55,47.6 225.55,48.36 RN7.4
  Bottom 0.152: v225.55,47.6 v225.55,38.71
A8
  Top 0.152: RN8.1 224.16,49.17 228.73,49.17 229.54,48.36 229.54,42.32 229.13,41.91 226.49,41.91 223.11,38.53 U1.64
A9  (via drill 0.25 pad 0.51)
  Top 0.152: v220.95,49.17 220.95,49.73 221.36,50.14 222.55,50.14 223.36,49.33 RN8.2 | v220.95,39.09 220.89,39.03 U1.65
  Bottom 0.152: v220.95,39.09 v220.95,49.17
A10  (via drill 0.25 pad 0.51)
  Top 0.152: v220.47,40.51 221.84,40.51 222.25,40.11 222.25,39.78 222.05,39.57 198.96,39.57 198.91,39.53 U1.66 | v222.55,47.6 v222.56,47.61 RN8.3
  Bottom 0.152: v222.55,47.6 222.55,49.55 222.15,49.96 220.88,49.96 220.47,49.55 v220.47,40.51
A11  (via drill 0.25 pad 0.51)
  Top 0.152: v221.77,41 220.04,41 219.07,40.03 U1.67 | v221.77,49.35 v221.76,49.35 RN8.4
  Bottom 0.152: v221.77,49.35 v221.77,41
A12  (via drill 0.25 pad 0.51)
  Top 0.152: v185.88,54.28 185.22,53.62 184.98,53.62 U1.106 | v194.03,52.98 194.18,52.83 218.34,52.83 219.94,51.23 R12.1
  Bottom 0.152: v194.03,52.98 194.03,51.03 193.62,50.62 187.58,50.62 185.88,52.32 v185.88,54.28
A13  (1 unrouted)
  Top 0.152: TP39.TP U1.107
A14  (via drill 0.25 pad 0.51)
  Top 0.152: v185.39,56.67 R73.1 | v183.82,51.21 183.98,51.36 U1.108
  Bottom 0.152: v183.82,51.21 183.82,52.22 185.39,53.8 v185.39,56.67
A15  (via drill 0.25 pad 0.51)
  Top 0.152: v183.26,56.67 R72.1 | v183.46,53.8 183.48,53.78 U1.109
  Bottom 0.152: v183.46,53.8 183.46,56.46 v183.26,56.67
A16
  Top 0.152: TP42.TP 188.48,54.22 U1.99
A17  (via drill 0.25 pad 0.51)
  Top 0.152: v188.67,55.17 188.16,55.17 TP43.TP | v188.14,51.21 187.98,51.37 U1.100
  Bottom 0.152: v188.14,51.21 188.14,54.63 v188.67,55.17
A18
  Top 0.152: TP44.TP | TP44.TP U1.101
A19
  Top 0.152: TP48.TP 172.49,24.33 172.49,25.68 172.48,25.69 U1.2
A20
  Top 0.152: TP49.TP 172.99,22.93 172.99,25.6 172.98,25.62 U1.3
A22
  Top 0.152: TP14.TP 173.94,25.43 173.98,25.46 U1.5
A23
  Top 0.152: TP15.TP 171.98,25.19 U1.1
A24
  Top 0.152: U1.156 170,39.04 TP26.TP
A_3V3  (via drill 0.25 pad 0.51)  (1 unrouted)
  Top 0.152: v287.73,68.56 287.73,69.09 296.44,69.09 296.44,81.31 L2.2 | v287.73,67.16 LED1.A
  Top 0.61: L2.2 294.67,84.96 275.77,84.96 275.77,83.8 | 275.77,83.8 R31.1 | 275.77,83.8 273.1,83.8 arc-90 272.72,83.42 C58.1 266.02,83.42 L6.1
  Bottom 0.152: v287.73,68.56 v287.73,67.16
A_5V0  (via drill 0.25 pad 0.51)
  Top 0.152: R33.1 275.92,59 | 272.81,59.02 272.75,59.08 C92.1 | C93.1 269.01,59.08 | v282.96,60.71 282.96,61.77 287.83,61.77 287.83,64.87 LED5.A
  Top 0.508: 272.81,59.02 R33.1 275.92,60.71 v282.96,60.71 | 269.01,59.08 C92.1 | L3.2 294.69,60.76 v292.05,60.76 | C93.1 266.12,59.03 L1.1
  Bottom 0.508: v292.05,60.76 arc-90 292,60.71 v282.96,60.71
AC_DC_IN  (via drill 0.25 pad 0.51)
  Top 0.152: v280.77,50.52 | C91.1 268.94,50.89
  Top 0.254: C1.+ 291.35,14.46 C50.1
  Top 0.406: 274.55,7.42 274.07,7.9 | 274.07,15.04 274.1,15.07
  Top 0.508: v280.77,50.52 C90.1 268.94,50.52 C91.1 268.47,50.13 C89.1 | v280.77,50.52 U$9.7 | C57.1 268.67,74.84 C55.1
  Top 0.61: B1.VDD 277.23,7.42 274.55,7.42 274.02,7.42 271.68,5.08 JP3.2 | C28.+ 283.46,18.16 C6.+ 280.38,15.07 C7.1 274.1,15.07 | 274.07,7.9 274.07,15.04 | v280.77,66.98 277.37,66.98 277.37,70.38 | 277.37,70.38 277.37,70.54 272.64,70.54 C56.1 269.09,75.18 C57.1 | U$7.7 280.54,70.38 277.37,70.38
  Bottom 0.254: C1.+ 287.66,18.16 287.4,18.42
  Bottom 0.61: 287.66,18.16 C28.+ | v280.77,66.98 v280.77,50.52 285.27,50.52 287.4,48.39 287.4,18.42
AC_IN1
  Top 0.61: J2.2 291.89,7.48 B1.AC1
AC_IN2
  Top 0.61: J2.1 292.14,2.38 B1.AC2
AGND  (via drill 0.25 pad 0.51)
  Top 0.152: C90.2 272.29,53.32 | C50.2 291.1,12.76 C1.- 286.79,11.2 286.69,11.3 C6.- 280.19,11.3 | 280.19,11.3 278.32,13.17 C7.2 | R34.2 275.84,51.23 v279.5,51.23 U$9.6 | 272.29,56.23 C92.2 | 272.66,76.62 v272.64,76.63 C56.2 | 268.94,56.23 C93.2 | 272.64,80.62 C59.2 | C57.2 269.14,78.06 | 280.19,11.3 280.19,2.59 279.97,2.38 B1.VSS | U$7.6 279.48,76.76 | 279.48,78.79 U$7.9 | v279.5,67.95 293.41,67.95 R2.2 293.43,67.16 R5.1
  Top 0.203: R34.2 275.81,52.09 274.7,52.09 274.7,52.88 274.27,53.31 C90.2 | 279.48,78.79 279.27,78.59 U$7.6 279.27,74.84 R32.2
  Top 0.508: C93.2 272.29,56.23 272.29,53.32 | C56.2 272.64,80.62 | 269.14,78.06 C58.2 C59.2 274.93,79.35 275.49,78.79 279.48,78.79 | U$9.9 279.7,55.52 | C92.2 274.27,56.28 275.03,55.52 279.7,55.52 | C57.2 266.4,78.06 | R39.1 266.02,78.06 266.4,78.06 | 266.4,78.06 C55.2 | R6.1 267.16,56.23 268.94,56.23 C91.2 267.81,53.39 C89.2 | 279.7,55.52 v281.99,55.52 | v289.05,55.52 U$13.A | U$7.9 279.91,79.5 v282.14,79.5 | v288.98,79.5 U$8.A
  Bottom 0.152: 279.81,23.24 279.5,23.55 v279.5,51.23 v279.5,67.95 272.64,67.95 v272.64,76.63 | C6.- 279.5,13.49 279.5,22.94 279.81,23.24 | 279.81,23.24 C28.-
  Bottom 0.508: v281.99,55.52 v289.05,55.52 | v282.14,79.5 v288.98,79.5
  other vias: 277.06,10.64 285.5,11.46 269.19,22.48 277.5,20.27 269.75,15.8 274.73,45.01 284.51,41.71 285.34,36.04 285.34,31.22 270.31,39.01 268.12,32.87 290.37,62.71 295.1,66.17 292.58,58.93 284.38,83.41 292.46,83.36 277.83,79.22 278.41,73.76 275.56,72.52 267.23,72.11 270.15,69.82 274.5,67.69 278.56,64.03 274.09,62.43 293.57,74.12 284.89,69.52 267.74,2.29 272.69,2.87 288.7,4.88 294.69,10.97 291.01,23.37 294.54,18.49 295.66,4.75 294.89,49.2 295.27,44.93 295.43,28.85 295.3,62.81 284.1,65.07 266.5,56.92 266.42,53.42 274.5,55.63 267.74,44.98 273.53,28.8 291.11,35.08 285.37,58.75 277.29,4.83 283.64,4.88 295.66,23.27
  pour Top (isolate 0.508): 265.71,85.85 297.71,85.85 297.71,0 265.71,0
  pour Bottom (isolate 0.508): 265.71,85.85 297.71,85.85 297.71,0 265.71,0
BOOT0  (via drill 0.25 pad 0.51)
  Top 0.152: v159.99,29.84 159.99,33.48 161.59,35.08 165.56,35.08 166.61,34.03 U1.166 | v159.69,10.9 168.88,10.9 169.09,10.69 R11.2
  Bottom 0.152: v159.69,10.9 159.69,29.54 v159.99,29.84
BUZZER  (via drill 0.25 pad 0.51)
  Top 0.152: v209.52,63.14 237.11,63.14 237.33,63.36 R43.2 | v180.52,56.03 181.51,56.03 181.91,56.44 181.91,60.17 182.32,60.58 206.22,60.58 206.63,60.98 v206.63,62.28 | v180.52,53.8 180.48,53.76 U1.115
  Bottom 0.152: v206.63,62.28 208.66,62.28 v209.52,63.14 | v180.52,53.8 v180.52,56.03
CLK
  Top 0.152: R14.2 214.82,10.59 Y1.3
CLK_24MHZ  (via drill 0.25 pad 0.51)
  Top 0.152: v212.7,16.21 212.7,10.57 R14.1 | v212.7,22.1 187.58,22.1 185.98,23.7 U1.29
  Bottom 0.152: v212.7,22.1 v212.7,16.21
CLK_RTC_IN  (1 unrouted)
  Top 0.152: R13.1 172.8,19 175.98,22.18 U1.9
CLK_RTC_OUT  (via drill 0.25 pad 0.51)
  Top 0.152: v176.56,20.68 v176.56,20.67 176.48,20.67 U1.10 | v176.56,16.23 R74.1
  Bottom 0.152: v176.56,16.23 v176.56,20.68
CS  (via drill 0.25 pad 0.51)
  Top 0.152: RN11.5 160.39,76.34 162,74.74 U$19.P2 177.26,74.74 v177.93,74.07 | v183.57,44.86 v177.93,44.86 | v174.12,29.01 174.68,29.01 175.48,28.2 U1.8
  Bottom 0.152: v177.93,44.86 v177.93,74.07 | v174.12,29.01 174.12,30.02 174.93,30.84 181.97,30.84 183.57,32.44 v183.57,44.86
D0  (via drill 0.25 pad 0.51)
  Top 0.152: v205.71,31.39 205.71,28.04 207.31,26.44 208,26.44 208.4,26.84 RN4.8 | v191.44,49.84 186.77,49.84 186.36,50.24 186.36,50.85 185.98,51.23 U1.104
  Bottom 0.152: v191.44,49.84 191.44,32.16 193.04,30.56 204.88,30.56 v205.71,31.39
D1  (via drill 0.25 pad 0.51)
  Top 0.152: v207.16,28.96 208.99,28.96 209.2,28.75 RN4.7 | v185.32,51.21 185.48,51.37 U1.105
  Bottom 0.152: v185.32,51.21 185.32,49.35 189.66,45.01 189.66,30.56 191.26,28.96 v207.16,28.96
D2  (via drill 0.25 pad 0.51)
  Top 0.152: v190.96,45.95 190.88,46.03 U1.142 | v209.83,28.88 210,28.71 RN4.6
  Bottom 0.152: v209.83,28.88 209.83,29.54 209.63,29.74 192.56,29.74 190.96,31.34 v190.96,45.95
D3  (via drill 0.25 pad 0.51)
  Top 0.152: v190.32,45.47 190.26,45.53 U1.143 | v209.19,27.13 210.64,27.13 210.8,27.29 RN4.5
  Bottom 0.152: v209.19,27.13 209.19,27.84 207.59,29.44 191.92,29.44 190.32,31.04 v190.32,45.47
D4  (via drill 0.25 pad 0.51)
  Top 0.152: v198.12,40.51 198.11,40.53 U1.68 | v210.31,26.16 212.01,26.16 212.82,26.97 RN3.8
  Bottom 0.152: v210.31,26.16 210.31,34.16 203.96,40.51 v198.12,40.51
D5  (via drill 0.25 pad 0.51)
  Top 0.152: v199.42,41 199.38,41.03 U1.69 | v213.64,26.65 213.62,26.66 RN3.7
  Bottom 0.152: v213.64,26.65 212.22,26.65 210.62,28.25 210.62,34.65 204.27,41 v199.42,41
D6  (via drill 0.25 pad 0.51)
  Top 0.152: v214.3,26.47 214.3,27.77 214.42,27.89 RN3.6 | v201.09,41.5 201.07,41.53 U1.70
  Bottom 0.152: v201.09,41.5 204.72,41.5 211.07,35.15 211.07,31.07 214.3,27.84 v214.3,26.47
D7  (via drill 0.25 pad 0.51)
  Top 0.152: v216.56,40.89 202.44,40.89 202.03,41.3 202.03,41.43 200.43,43.03 U1.73 | v216.56,28.02 216.55,28.01 RN3.5
  Bottom 0.152: v216.56,28.02 v216.56,40.89
D8  (via drill 0.25 pad 0.51)
  Top 0.152: v215.57,49.35 215.57,48.61 215.55,48.59 RN2.8 | v200.66,44.22 199.97,43.53 U1.74
  Bottom 0.152: v200.66,44.22 210.44,44.22 v215.57,49.35
D9  (via drill 0.25 pad 0.51)
  Top 0.152: v214.76,49.35 214.76,48.6 214.75,48.59 RN2.7 | v198.81,44.86 v198.81,44.85 198.81,44.25 198.59,44.03 U1.75
  Bottom 0.152: v198.81,44.86 210.26,44.86 v214.76,49.35
D10
  Top 0.152: U1.76 197.33,44.53 197.54,44.73 197.54,48.54 199.14,50.14 213.16,50.14 213.95,49.35 RN2.6
D11
  Top 0.152: U1.77 197.03,45.03 197.23,45.23 197.23,48.84 198.83,50.44 215.21,50.44 216.05,49.61 216.05,47.93 215.9,47.78 213.15,47.78 RN2.5
D12  (via drill 0.25 pad 0.51)
  Top 0.152: v194.01,43.05 194.01,45.31 194.22,45.53 U1.78 | v203.86,43.05 v203.85,43.06 203.85,44.6 207.03,47.78 210.83,47.78 RN1.8
  Bottom 0.152: v203.86,43.05 v194.01,43.05
D13  (via drill 0.25 pad 0.51)
  Top 0.152: v200.61,49.66 209.63,49.66 210.03,49.26 RN1.7 | v191.9,51.11 190.2,51.11 189.98,51.32 U1.96
  Bottom 0.152: v191.9,51.11 191.9,55.45 192.3,55.86 197.79,55.86 198.2,55.45 198.2,47.95 199.01,47.14 200.61,48.74 v200.61,49.66
D14  (via drill 0.25 pad 0.51)
  Top 0.152: v199.69,51.56 194.74,51.56 193.6,50.42 189.89,50.42 189.48,50.83 U1.97 | v199.69,49.17 209.23,49.17 RN1.6
  Bottom 0.152: v199.69,49.17 v199.69,51.56
D15  (via drill 0.25 pad 0.51)
  Top 0.152: v188.98,51.21 188.98,51.84 U1.98 | v198.68,48.46 208.43,48.46 RN1.5
  Bottom 0.152: v198.68,48.46 198.68,55.75 198.27,56.16 191.52,56.16 191.11,55.75 191.11,53.34 v188.98,51.21
DAC1_OUT1
  Top 0.152: U$10.2 R64.1 R21.1 252.78,36.5 203.4,36.5 202.59,35.69 202.59,34.37 199.41,31.19 197.41,31.19 197.07,31.53 U1.50
DAC1_OUT2
  Top 0.152: TP18.TP 196.67,32.03 U1.51
FMC_NBL0  (via drill 0.25 pad 0.51)
  Top 0.152: v167.92,32.51 169.33,32.51 169.34,32.53 U1.169 | v163.25,27.13 v166.01,27.13 | v163.25,29.01 163.25,31.93 163.45,32.13 R71.1
  Bottom 0.152: v166.01,27.13 167.92,29.03 v167.92,32.51 | v163.25,29.01 v163.25,27.13
FMC_NBL1
  Top 0.152: R70.1 164.95,34.29 167.21,32.03 U1.170
GND  (via drill 0.25 pad 0.51, 4.06 pad 6.6)  (2 unrouted)
  Top 0.152: 196.94,11.35 T3.E 196.94,8.38 196.54,7.98 184,7.98 183.59,7.57 SV5.3 183.59,3.73 166.65,3.73 166.5,3.89 JP1.1 166.5,8.48 164.9,10.08 v158.09,10.08 158.09,8.79 C5.2 | v196.14,11.35 196.94,11.35 | 242.33,65.38 T1.E | v243.26,65.38 242.33,65.38 | 245.13,25.08 245.13,29.52 R26.2 249.78,29.52 250.09,29.21 251.18,29.21 252.78,30.81 U$10.5 v252.78,34.06 | 243.9,24.51 244.48,25.08 245.13,25.08 | 213.21,42.16 212.9,41.86 209.18,41.86 208.4,42.65 | 208.4,42.65 206.96,42.65 206.8,42.81 U$15.54 | C37.- 245.01,8.81 245.01,6.67 T4.E 244.06,6.8 R53.1 | 151.99,65.08 163.63,65.08 C38.- v174.7,62.36 | C39.- 221.56,61.16 218.34,57.94 214.66,57.94 214.35,57.63 | v231.62,53.44 233.06,53.44 233.46,53.85 C26.2 233.46,57.28 C29.2 239.12,57.28 242.3,60.46 R35.1 v243.23,63.22 | 261.98,63.93 261.98,64.39 261.98,64.77 | C5.2 157.32,9.55 157.11,9.75 v146.63,9.75 | R6.2 262.61,55.12 262.05,55.68 C11.- 254.61,55.68 254.04,56.25 C17.2 | R39.2 257.28,78.41 257.25,78.38 C3.- 254.58,78.38 253.99,78.98 C16.2 | 182.17,29.31 182.6,29.74 189.66,29.74 | 262.74,19.05 257.18,19.05 257.02,19.2 R63.1 R62.1 250.1,19.95 v250.09,19.96 IC1.3 | 189.66,29.74 191.9,31.98 v194.16,31.98 194.16,30.68 194.31,30.53 U1.48 | v111.46,10.64 BT1.2 | 208.4,42.65 U$15.52 | C23.1 209.74,72.96 208.94,72.16 C47.1 208.94,70.68 C32.1 207.21,71.75 v207.19,71.78 C21.1 | C5.2 156.13,8.79 155.34,7.99 S1.1 | v146.66,64.77 151.69,64.77 151.99,65.08 | 245.13,25.08 C30.2 | 211.74,57.63 209.19,57.63 208.79,58.04 C31.2 | R21.2 v252.78,38.76 252.78,41.08 252.98,41.29 T7.E 255.83,41.29 R44.2 | C62.1 221.89,70.93 221.69,70.72 C49.1 220.55,70.53 C33.1 218.87,71.22 v218.95,71.3 218.95,71.78 218.85,71.78 C60.1 218.16,72.38 218.01,72.53 218.01,74.12 217.45,74.12 U$5.1
  Top 0.152: 242.33,65.38 C45.1 | 196.94,11.35 R30.1 | 211.74,57.63 212.04,57.94 214.05,57.94 214.35,57.63 | v174.7,62.36 174.7,61.39 175.01,61.09 C9.2 | 213.21,42.16 213.51,41.86 v215.6,41.86 216.38,41.86 217.2,42.67 U$15.41 | C2.2 205.04,17.36 204.62,16.94 v204.06,16.94 v196.9,16.94 196.08,16.94 R60.1 | C27.1 260.77,23.44 T6.E | C36.1 198.07,70.5 C46.1 199.72,71.53 200.13,71.93 v200.66,71.93 C20.1 | C52.1 198.04,71.5 197.89,71.35 v196.67,71.35 U$3.1 | 228.24,71.45 v226.8,71.45 U$6.1 | 228.24,71.45 229.97,71.45 C51.1 | C15.2 253.02,69.04 253.67,69.04 254.08,69.44 v254.08,70.21 254.09,70.22 R61.2 255.04,70.99 257.4,70.99 257.81,71.4 U$1.2 | v229.24,35.71 229.24,35.5 229.49,35.24 C14.2 230.15,35.41 234.21,35.41 234.42,35.21 234.42,30.76 234.01,30.35 231.5,30.35 R55.1 233.47,29.61 T5.E 233.47,27.53 235.06,25.94 C34.2 237.44,25.96 241.29,25.96 | 228.24,71.45 C35.1 | v158.09,18.82 C24.1 | v195.94,54.41 199.72,54.41 199.94,54.62 C10.2 | 228.24,71.45 C63.1 | C48.1 v191.44,71.25 190.16,69.97 U$19.G2 | 241.91,24.51 241.71,24.71 | v217.96,15.72 218.47,15.21 Y1.2 218.47,10.07 C12.2 C8.2 | 151.99,65.08 151.99,75.87 X5.5 | U$19.G2 180,67.66 v174.7,62.36 | v174.7,83.72 175.29,83.13 175.29,79.14 U$19.P6 | v174.7,83.72 U$19.G3 | v174.7,83.72 U$19.G4 | 214.35,57.63 214.35,56.65 214.34,56.64 IC2.8 | 211.74,57.63 IC2.4 211.74,55.55 211.94,55.35 212.17,55.35 212.39,55.57 IC2.5 | U$19.G2 U$19.G1 | v211.86,34.16 210.97,34.16 210.8,33.99 U$15.6 | 213.21,42.16 213.2,42.18 U$15.46 | J1.1 86.2,8.31 85.2,8.31 J1.3 v85.2,5.96 v85.22,5.94 | 175.29,50.72 181.25,50.72 181.48,50.95 U1.113 | 182.17,29.31 178.69,29.31 178.48,29.1 U1.14
  Top 0.152: 174.98,49.84 174.68,49.53 U1.135 | 189.66,29.74 189.97,29.44 U1.37 | 182.17,29.31 182.48,29 U1.22 | v186.99,50.32 186.98,50.34 U1.102 | 175.29,50.72 174.98,51.03 U1.126 | v193.14,51.21 192.98,51.37 U1.90 | v215.6,37.49 v229.24,37.49 229.24,40.83 229.44,41.03 C13.2 230.94,41.03 C42.2 | 174.98,49.84 174.98,50.42 175.29,50.72 | 174.98,49.84 175.29,49.53 v175.97,49.53 | v194.16,37.03 194.16,37.03 U1.61 | v176.63,49.53 185.01,49.53 v185.8,50.32 | v228.42,43.1 228.42,43.08 228.17,42.82 227.6,42.82 U$15.28 | v172.57,41.86 172.57,42.62 172.16,43.03 U1.148 | v72.21,5.94 v72.2,5.95 J1.29 | v171.4,41.86 171.4,38.23 171.2,38.03 U1.158 | v101.22,2.79 101.23,2.78 C41.2 | v62.05,6.45 62.05,12.94 R38.2 | 44.32,2.16 42.72,3.76 J3.2 v42.72,10.57 | v194.16,41.96 194.22,42.03 U1.71 | v158.09,16.31 C25.1 | v204.14,15.72 C4.2 | v205.74,71.63 U$4.1 | v68.71,6.45 v68.7,6.46 J1.36 | v215.6,34.16 | v215.6,34.16 U$15.12
  Top 0.203: IC1.3 250.09,29.21
  Top 0.254: 243.9,24.51 U$17.2 241.91,24.51 | 241.71,24.71 241.71,25.55 241.29,25.96
  Top 0.406: 261.98,64.77 261.98,64.59 | C18.2 263.25,67.72 263.25,64.77 | 257.81,71.4 v257.81,65.05 | v260.02,64.97 260.02,64.39 261.98,64.39
  Top 0.61: v268.83,9.78 262.74,9.78 262.74,19.05 262.74,23.42 260.74,23.42 C27.1
  Top 1.016: v268.83,64.77 263.25,64.77 261.98,64.77
  Bottom 0.152: 255.83,70.51 256.9,69.44 256.9,56.82 C11.- 255.75,41.73 v252.78,38.76 v252.78,34.06 | 194.82,51.56 195.73,51.56 195.94,51.36 195.94,48.69 193.52,46.28 193.52,42.6 v194.16,41.96 v194.16,37.03 v194.16,31.98 | v185.8,50.32 v186.99,50.32 194.41,50.32 194.82,50.72 194.82,51.56 | 94.21,5.94 v85.22,5.94 v72.21,5.94 69.22,5.94 v68.71,6.45 v62.05,6.45 62.03,6.45 62.03,3.28 v61.09,2.34 | C3.- 255.83,70.51 | 94.21,5.94 94.21,5.61 97.38,2.44 C40.- 99.7,2.44 100.05,2.79 v101.22,2.79 | v196.9,16.94 196.9,12.12 v196.14,11.35 | v158.09,18.82 v158.09,16.31 v158.09,10.08 | 94.21,5.94 94.51,6.25 v94.51,11.3 110.79,11.3 v111.46,10.64 112.34,9.75 v146.63,9.75 146.63,17.65 146.96,17.98 SV1.20 SV1.18 SV1.16 SV1.14 SV1.12 SV1.10 SV1.8 SV1.6 SV1.4 148.26,51.69 148.26,56.39 146.66,57.99 v146.66,64.77 | 194.51,53.16 194.51,51.87 194.82,51.56 | v254.08,70.21 255.52,70.21 255.83,70.51 | 194.51,53.16 194.82,53.47 195.94,53.47 v195.94,54.41 | v229.24,35.71 v229.24,37.49 228.42,38.3 v228.42,43.1 231.62,46.3 v231.62,53.44 231.62,57.99 228.45,61.16 C39.- 225.73,70.38 v226.8,71.45 226.16,72.09 219.74,72.09 v218.95,71.3 207.67,71.3 v207.19,71.78 206.38,71.78 206.22,71.63 v205.74,71.63 201.45,71.63 201.14,71.93 v200.66,71.93 197.26,71.93 v196.67,71.35 192.48,71.35 192.38,71.25 v191.44,71.25 | v243.26,65.38 243.23,65.35 v243.23,63.22 | v217.96,15.72 v204.14,15.72 204.14,16.87 v204.06,16.94 | v211.86,34.16 v215.6,34.16 v215.6,37.49 v215.6,41.86 | 194.51,53.16 194.51,53.26 194.31,53.47 193.55,53.47 193.14,53.06 v193.14,51.21 | v174.7,83.72 v174.7,62.36 174.7,61.04 174.24,60.58 174.24,52.5 175.9,50.85 176.23,50.85 176.63,50.44 v176.63,49.53 v175.97,49.53 175.97,45.26 v172.57,41.86 v171.4,41.86
  Bottom 0.152: C37.- 252.58,17.48 v250.09,19.96 | v42.72,10.57 42.16,11.12 v6.38,11.3
  Bottom 0.406: v257.81,65.05 257.81,64.97 v260.02,64.97
  other vias: 249.5,53.11 253.19,47.12 260.25,55.17 260.58,38.05 261.39,50.88 232.38,82.85 238.15,68.12 233.58,71.25 232.66,77.67 260.27,83.52 247.47,83.29 260.27,76.94 250.16,67.64 255.96,62.2 250.85,59.99 262.25,62 220.14,75.13 218.92,79.58 209.07,79.71 210.21,73.05 186.69,82.35 192.23,62.76 186.94,73.66 180.01,63.6 186.77,67.67 179.55,79.98 166.5,83.79 144.42,69.29 155.02,82.98 158.11,61.19 155.09,69.8 154.46,61.62 146.99,83.85 168.2,66.09 169.7,61.44 230.56,73.3 242.11,59.21 237.31,60.35 235.99,52.81 221.06,61.52 219.63,56.08 228.63,61.67 227.86,55.93 232.33,44.17 222.66,52.04 231.95,49.78 248.89,39.32 249.91,34.59 235.86,33.68 249.89,31.12 250.42,27.08 230.1,26.57 230.38,23.32 235.99,28.09 239.57,15.21 233.55,20.45 263.17,24.38 262.76,17.17 260.15,20.5 262.41,7.8 246.89,10.74 246.71,16.46 252.6,21.46 257.2,15.67 247.78,5.61 261.44,2.41 242.85,2.44 222.17,12.55 224.13,17.48 231.34,15.11 234.67,10.57 229.62,6.6 203.43,18.92 209.88,17.81 215.98,17.63 210.72,10.19 203.15,9.63 204.17,5.28 213.13,1.8 191.13,1.8 176.3,1.75 189.26,8.1 192.74,6.43 228.8,40.72 234.44,40.94 211.61,59.31 208.94,83.59 186.49,63.65 205.13,34.54 231.65,35.28 166.12,8.28 163.83,5.94 158.04,5.36 155.22,8.94 152.58,5.84 152.3,11.86 135.64,11.43 140.67,11.48 138.38,9.22 122.81,10.19 116.66,5.77 83.72,4.42 71.81,4.45 78.33,4.34 67.44,28.42 47.65,28.5 33.1,28.5 3.94,26.34 23.11,26.34 13.79,23.09 4.32,17.17 23.19,16.87 3.58,3 21.56,2.64 36.47,11.05 14.86,14.58 13.49,6.88 56.44,13.79 57.78,4.22 53.8,7.87 98.76,13.31 129.34,5.72 144.35,77.55 171.4,73.18 167.26,73.08 157.33,79.55 158.37,76.07 191.39,69.47 187.58,78.71 215.98,70.54 225.27,70.43 195.4,70.26 204.17,70.82 253.77,83.52 259.69,61.09 245.44,39.83 249.4,41.61 250.75,37.87 262.43,32.72 238.94,6.99 227,10.39 206.45,59.23 215.29,57.38 222.1,58.85 228.17,51.64 246.1,65.94 248.18,72.09 241.63,73.48 241.12,81.15 259.18,79.43 253.49,66.42 180.75,74.02 167.69,70.18 174.62,70.23 160.81,43.94 163.8,42.42 156.82,29.44 215.54,5.61 255.96,51.38 241.73,40.69 240.84,35.2 240.72,28.19 254.89,29.51 257.96,29.72 257.12,10.54 47.35,16.05 50.29,11.94 46.41,8.41 36.25,20.14
  pour Bottom (isolate 0.508): 0,0 0,30.1 141,30.1 141,85.85 263.93,85.85 263.93,0
  pour Top (isolate 0.508): 0,0 0,30.1 141,30.1 141,85.85 263.93,85.85 263.93,0
LCD_ADJ  (via drill 0.25 pad 0.51)
  Top 0.152: U$1.4 256.86,67.97 R37.2 256.55,65.3 253.38,62.13 248.97,62.13 242.62,55.78 242.62,55.04 235.85,48.27 235.85,39.98 232.67,36.8 201.5,36.8 199.9,35.2 v199.9,32.54 | v196.75,32.54 196.74,32.53 U1.52
  Bottom 0.152: v196.75,32.54 v199.9,32.54
LCD_B0  (via drill 0.25 pad 0.51)
  Top 0.152: v76.1,18.87 74.86,17.63 RN16.4 | v76.1,27.61 157.1,27.61 157.91,28.42 157.91,36.91 159.51,38.51 170,38.51 U1.157
  Bottom 0.152: v76.1,27.61 v76.1,18.87
LCD_B1  (via drill 0.25 pad 0.51)
  Top 0.152: v155.14,30.89 155.14,38.76 155.96,39.57 168.28,39.57 168.32,39.53 U1.155 | v155.14,18.26 88.57,18.26 86.97,16.66 86.97,13.77 86.56,13.36 74.27,13.36 74.06,13.57 RN16.3
  Bottom 0.152: v155.14,18.26 v155.14,30.89
LCD_B2  (via drill 0.25 pad 0.51)
  Top 0.152: v142.39,55.04 142.9,55.55 178.56,55.55 178.98,55.13 U1.118 | v76.58,19.96 74.85,19.96 73.26,18.37 RN16.2
  Bottom 0.152: v76.58,19.96 76.58,24.92 79.76,28.09 141.58,28.09 142.39,28.91 v142.39,55.04
LCD_B3  (via drill 0.25 pad 0.51)
  Top 0.152: v148.92,25.25 75.64,25.25 72.46,22.07 RN16.1 | v148.92,40.01 169.32,40.01 169.34,40.03 U1.154
  Bottom 0.152: v148.92,40.01 v148.92,25.25
LCD_B4  (via drill 0.25 pad 0.51)
  Top 0.152: v71.78,14.3 71.78,14.81 71.58,15.01 71.08,15.01 RN17.4 | v161.75,16.99 161.7,17.04 114.15,17.04 v113.51,16.41 | v161.75,27.74 164.8,27.74 166.4,29.34 166.4,29.72 167.2,30.53 U1.173
  Bottom 0.152: v113.51,16.41 87.1,16.41 84.99,14.3 v71.78,14.3 | v161.75,27.74 v161.75,16.99
LCD_B5  (via drill 0.25 pad 0.51)
  Top 0.152: v71.73,17.6 71.73,16.36 70.92,15.55 70.69,15.55 70.28,15.14 RN17.3 | v71.73,26.34 166.12,26.34 167.72,27.95 167.72,29.21 168.54,30.03 U1.174
  Bottom 0.152: v71.73,26.34 v71.73,17.6
LCD_B6  (via drill 0.25 pad 0.51)
  Top 0.152: v71.25,17.12 69.48,15.35 RN17.2 | v156.54,28.09 75.72,28.09 74.93,27.3 v71.25,27.3 | v156.54,24.77 166.98,24.77 168.58,26.37 168.58,29.31 168.79,29.53 U1.175
  Bottom 0.152: v71.25,27.3 v71.25,17.12 | v156.54,24.77 v156.54,28.09
LCD_B7  (via drill 0.25 pad 0.51)
  Top 0.152: v78.31,24.11 78.49,24.28 167.28,24.28 168.88,25.88 168.88,29.03 U1.176 | v68.68,15.19 v68.68,15.18 RN17.1
  Bottom 0.152: v68.68,15.19 77.5,15.19 78.31,16 v78.31,24.11
LCD_CLK  (via drill 0.25 pad 0.51)
  Top 0.152: v68.68,16.31 68.2,15.82 67.27,15.82 RN6.8 | v67.13,13.44 67.13,14.07 67.27,14.2 RN18.4 | v141.83,57.48 142.49,56.82 179.83,56.82 180.04,56.62 180.04,55.75 180.24,55.55 181.66,55.55 182.48,54.73 U1.111
  Bottom 0.152: v67.13,13.44 67.13,15.42 68.02,16.31 v68.68,16.31 68.68,26.26 71.86,29.44 141.43,29.44 141.83,29.84 v141.83,57.48
LCD_DE  (via drill 0.25 pad 0.51)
